VERSION 5.7 ;
  NOWIREEXTENSIONATPIN ON ;
  DIVIDERCHAR "/" ;
  BUSBITCHARS "[]" ;
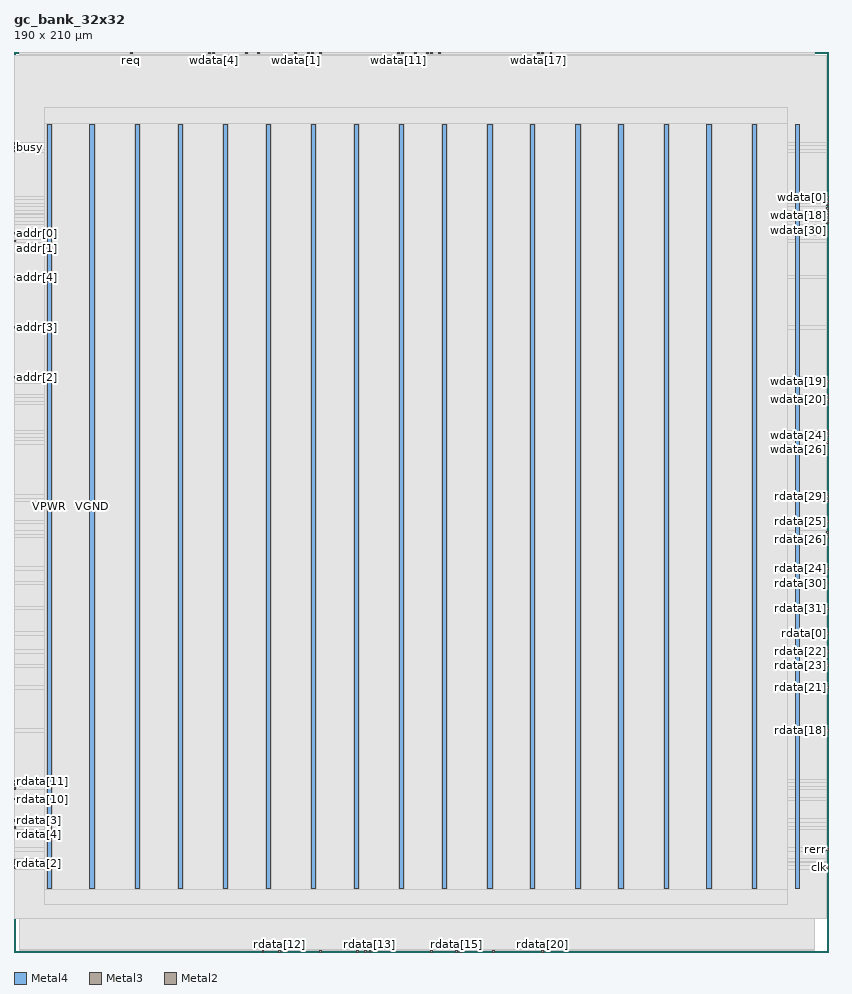
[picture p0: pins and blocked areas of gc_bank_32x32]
MACRO gc_bank_32x32
  CLASS BLOCK ;
  FOREIGN gc_bank_32x32 ;
  ORIGIN 0.000 0.000 ;
  SIZE 190.000 BY 210.000 ;
  PIN VGND
    DIRECTION INOUT ;
    USE GROUND ;
    PORT
      LAYER Metal4 ;
        RECT 17.710 14.900 18.710 193.000 ;
    END
    PORT
      LAYER Metal4 ;
        RECT 38.280 14.900 39.280 193.000 ;
    END
    PORT
      LAYER Metal4 ;
        RECT 58.850 14.900 59.850 193.000 ;
    END
    PORT
      LAYER Metal4 ;
        RECT 79.420 14.900 80.420 193.000 ;
    END
    PORT
      LAYER Metal4 ;
        RECT 99.990 14.900 100.990 193.000 ;
    END
    PORT
      LAYER Metal4 ;
        RECT 120.560 14.900 121.560 193.000 ;
    END
    PORT
      LAYER Metal4 ;
        RECT 141.130 14.900 142.130 193.000 ;
    END
    PORT
      LAYER Metal4 ;
        RECT 161.700 14.900 162.700 193.000 ;
    END
    PORT
      LAYER Metal4 ;
        RECT 182.270 14.900 183.270 193.000 ;
    END
  END VGND
  PIN VPWR
    DIRECTION INOUT ;
    USE POWER ;
    PORT
      LAYER Metal4 ;
        RECT 7.710 14.900 8.710 193.000 ;
    END
    PORT
      LAYER Metal4 ;
        RECT 28.280 14.900 29.280 193.000 ;
    END
    PORT
      LAYER Metal4 ;
        RECT 48.850 14.900 49.850 193.000 ;
    END
    PORT
      LAYER Metal4 ;
        RECT 69.420 14.900 70.420 193.000 ;
    END
    PORT
      LAYER Metal4 ;
        RECT 89.990 14.900 90.990 193.000 ;
    END
    PORT
      LAYER Metal4 ;
        RECT 110.560 14.900 111.560 193.000 ;
    END
    PORT
      LAYER Metal4 ;
        RECT 131.130 14.900 132.130 193.000 ;
    END
    PORT
      LAYER Metal4 ;
        RECT 151.700 14.900 152.700 193.000 ;
    END
    PORT
      LAYER Metal4 ;
        RECT 172.270 14.900 173.270 193.000 ;
    END
  END VPWR
  PIN addr[0]
    DIRECTION INPUT ;
    USE SIGNAL ;
    ANTENNAGATEAREA 0.180700 ;
    PORT
      LAYER Metal3 ;
        RECT 0.000 167.380 0.400 167.780 ;
    END
  END addr[0]
  PIN addr[1]
    DIRECTION INPUT ;
    USE SIGNAL ;
    ANTENNAGATEAREA 0.180700 ;
    PORT
      LAYER Metal3 ;
        RECT 0.000 165.700 0.400 166.100 ;
    END
  END addr[1]
  PIN addr[2]
    DIRECTION INPUT ;
    USE SIGNAL ;
    ANTENNAGATEAREA 0.180700 ;
    PORT
      LAYER Metal3 ;
        RECT 0.000 133.780 0.400 134.180 ;
    END
  END addr[2]
  PIN addr[3]
    DIRECTION INPUT ;
    USE SIGNAL ;
    ANTENNAGATEAREA 0.180700 ;
    PORT
      LAYER Metal3 ;
        RECT 0.000 145.540 0.400 145.940 ;
    END
  END addr[3]
  PIN addr[4]
    DIRECTION INPUT ;
    USE SIGNAL ;
    ANTENNAGATEAREA 0.180700 ;
    PORT
      LAYER Metal3 ;
        RECT 0.000 157.300 0.400 157.700 ;
    END
  END addr[4]
  PIN busy
    DIRECTION OUTPUT ;
    USE SIGNAL ;
    ANTENNADIFFAREA 0.708600 ;
    PORT
      LAYER Metal3 ;
        RECT 0.000 187.540 0.400 187.940 ;
    END
  END busy
  PIN clk
    DIRECTION INPUT ;
    USE SIGNAL ;
    ANTENNAGATEAREA 0.725400 ;
    PORT
      LAYER Metal3 ;
        RECT 189.600 19.540 190.000 19.940 ;
    END
  END clk
  PIN rdata[0]
    DIRECTION OUTPUT ;
    USE SIGNAL ;
    ANTENNADIFFAREA 0.708600 ;
    PORT
      LAYER Metal3 ;
        RECT 189.600 74.140 190.000 74.540 ;
    END
  END rdata[0]
  PIN rdata[10]
    DIRECTION OUTPUT ;
    USE SIGNAL ;
    ANTENNADIFFAREA 0.708600 ;
    PORT
      LAYER Metal3 ;
        RECT 0.000 35.500 0.400 35.900 ;
    END
  END rdata[10]
  PIN rdata[11]
    DIRECTION OUTPUT ;
    USE SIGNAL ;
    ANTENNADIFFAREA 0.708600 ;
    PORT
      LAYER Metal3 ;
        RECT 0.000 38.020 0.400 38.420 ;
    END
  END rdata[11]
  PIN rdata[12]
    DIRECTION OUTPUT ;
    USE SIGNAL ;
    ANTENNADIFFAREA 0.708600 ;
    PORT
      LAYER Metal2 ;
        RECT 61.720 0.000 62.120 0.400 ;
    END
  END rdata[12]
  PIN rdata[13]
    DIRECTION OUTPUT ;
    USE SIGNAL ;
    ANTENNADIFFAREA 0.708600 ;
    PORT
      LAYER Metal2 ;
        RECT 82.840 0.000 83.240 0.400 ;
    END
  END rdata[13]
  PIN rdata[14]
    DIRECTION OUTPUT ;
    USE SIGNAL ;
    ANTENNADIFFAREA 0.708600 ;
    PORT
      LAYER Metal2 ;
        RECT 81.880 0.000 82.280 0.400 ;
    END
  END rdata[14]
  PIN rdata[15]
    DIRECTION OUTPUT ;
    USE SIGNAL ;
    ANTENNADIFFAREA 0.708600 ;
    PORT
      LAYER Metal2 ;
        RECT 103.000 0.000 103.400 0.400 ;
    END
  END rdata[15]
  PIN rdata[16]
    DIRECTION OUTPUT ;
    USE SIGNAL ;
    ANTENNADIFFAREA 0.708600 ;
    PORT
      LAYER Metal2 ;
        RECT 97.240 0.000 97.640 0.400 ;
    END
  END rdata[16]
  PIN rdata[17]
    DIRECTION OUTPUT ;
    USE SIGNAL ;
    ANTENNADIFFAREA 0.708600 ;
    PORT
      LAYER Metal2 ;
        RECT 103.960 0.000 104.360 0.400 ;
    END
  END rdata[17]
  PIN rdata[18]
    DIRECTION OUTPUT ;
    USE SIGNAL ;
    ANTENNADIFFAREA 0.708600 ;
    PORT
      LAYER Metal3 ;
        RECT 189.600 51.460 190.000 51.860 ;
    END
  END rdata[18]
  PIN rdata[19]
    DIRECTION OUTPUT ;
    USE SIGNAL ;
    ANTENNADIFFAREA 0.708600 ;
    PORT
      LAYER Metal2 ;
        RECT 111.640 0.000 112.040 0.400 ;
    END
  END rdata[19]
  PIN rdata[1]
    DIRECTION OUTPUT ;
    USE SIGNAL ;
    ANTENNADIFFAREA 0.708600 ;
    PORT
      LAYER Metal2 ;
        RECT 79.960 0.000 80.360 0.400 ;
    END
  END rdata[1]
  PIN rdata[20]
    DIRECTION OUTPUT ;
    USE SIGNAL ;
    ANTENNADIFFAREA 0.708600 ;
    PORT
      LAYER Metal2 ;
        RECT 123.160 0.000 123.560 0.400 ;
    END
  END rdata[20]
  PIN rdata[21]
    DIRECTION OUTPUT ;
    USE SIGNAL ;
    ANTENNADIFFAREA 0.708600 ;
    PORT
      LAYER Metal3 ;
        RECT 189.600 61.540 190.000 61.940 ;
    END
  END rdata[21]
  PIN rdata[22]
    DIRECTION OUTPUT ;
    USE SIGNAL ;
    ANTENNADIFFAREA 0.708600 ;
    PORT
      LAYER Metal3 ;
        RECT 189.600 69.940 190.000 70.340 ;
    END
  END rdata[22]
  PIN rdata[23]
    DIRECTION OUTPUT ;
    USE SIGNAL ;
    ANTENNADIFFAREA 0.708600 ;
    PORT
      LAYER Metal3 ;
        RECT 189.600 66.580 190.000 66.980 ;
    END
  END rdata[23]
  PIN rdata[24]
    DIRECTION OUTPUT ;
    USE SIGNAL ;
    ANTENNADIFFAREA 0.708600 ;
    PORT
      LAYER Metal3 ;
        RECT 189.600 89.260 190.000 89.660 ;
    END
  END rdata[24]
  PIN rdata[25]
    DIRECTION OUTPUT ;
    USE SIGNAL ;
    ANTENNADIFFAREA 0.708600 ;
    PORT
      LAYER Metal3 ;
        RECT 189.600 100.180 190.000 100.580 ;
    END
  END rdata[25]
  PIN rdata[26]
    DIRECTION OUTPUT ;
    USE SIGNAL ;
    ANTENNADIFFAREA 0.708600 ;
    PORT
      LAYER Metal3 ;
        RECT 189.600 97.660 190.000 98.060 ;
    END
  END rdata[26]
  PIN rdata[27]
    DIRECTION OUTPUT ;
    USE SIGNAL ;
    ANTENNADIFFAREA 0.708600 ;
    PORT
      LAYER Metal3 ;
        RECT 189.600 96.820 190.000 97.220 ;
    END
  END rdata[27]
  PIN rdata[28]
    DIRECTION OUTPUT ;
    USE SIGNAL ;
    ANTENNADIFFAREA 0.708600 ;
    PORT
      LAYER Metal3 ;
        RECT 189.600 105.220 190.000 105.620 ;
    END
  END rdata[28]
  PIN rdata[29]
    DIRECTION OUTPUT ;
    USE SIGNAL ;
    ANTENNADIFFAREA 0.708600 ;
    PORT
      LAYER Metal3 ;
        RECT 189.600 106.060 190.000 106.460 ;
    END
  END rdata[29]
  PIN rdata[2]
    DIRECTION OUTPUT ;
    USE SIGNAL ;
    ANTENNADIFFAREA 0.708600 ;
    PORT
      LAYER Metal3 ;
        RECT 0.000 20.380 0.400 20.780 ;
    END
  END rdata[2]
  PIN rdata[30]
    DIRECTION OUTPUT ;
    USE SIGNAL ;
    ANTENNADIFFAREA 0.708600 ;
    PORT
      LAYER Metal3 ;
        RECT 189.600 85.900 190.000 86.300 ;
    END
  END rdata[30]
  PIN rdata[31]
    DIRECTION OUTPUT ;
    USE SIGNAL ;
    ANTENNADIFFAREA 0.708600 ;
    PORT
      LAYER Metal3 ;
        RECT 189.600 80.020 190.000 80.420 ;
    END
  END rdata[31]
  PIN rdata[3]
    DIRECTION OUTPUT ;
    USE SIGNAL ;
    ANTENNADIFFAREA 0.708600 ;
    PORT
      LAYER Metal3 ;
        RECT 0.000 30.460 0.400 30.860 ;
    END
  END rdata[3]
  PIN rdata[4]
    DIRECTION OUTPUT ;
    USE SIGNAL ;
    ANTENNADIFFAREA 0.708600 ;
    PORT
      LAYER Metal3 ;
        RECT 0.000 28.780 0.400 29.180 ;
    END
  END rdata[4]
  PIN rdata[5]
    DIRECTION OUTPUT ;
    USE SIGNAL ;
    ANTENNADIFFAREA 0.708600 ;
    PORT
      LAYER Metal3 ;
        RECT 0.000 21.220 0.400 21.620 ;
    END
  END rdata[5]
  PIN rdata[6]
    DIRECTION OUTPUT ;
    USE SIGNAL ;
    ANTENNADIFFAREA 0.708600 ;
    PORT
      LAYER Metal2 ;
        RECT 71.320 0.000 71.720 0.400 ;
    END
  END rdata[6]
  PIN rdata[7]
    DIRECTION OUTPUT ;
    USE SIGNAL ;
    ANTENNADIFFAREA 0.708600 ;
    PORT
      LAYER Metal2 ;
        RECT 57.880 0.000 58.280 0.400 ;
    END
  END rdata[7]
  PIN rdata[8]
    DIRECTION OUTPUT ;
    USE SIGNAL ;
    ANTENNADIFFAREA 0.708600 ;
    PORT
      LAYER Metal3 ;
        RECT 0.000 19.540 0.400 19.940 ;
    END
  END rdata[8]
  PIN rdata[9]
    DIRECTION OUTPUT ;
    USE SIGNAL ;
    ANTENNADIFFAREA 0.708600 ;
    PORT
      LAYER Metal3 ;
        RECT 0.000 38.860 0.400 39.260 ;
    END
  END rdata[9]
  PIN req
    DIRECTION INPUT ;
    USE SIGNAL ;
    ANTENNAGATEAREA 0.180700 ;
    PORT
      LAYER Metal2 ;
        RECT 27.160 209.600 27.560 210.000 ;
    END
  END req
  PIN rerr
    DIRECTION OUTPUT ;
    USE SIGNAL ;
    ANTENNADIFFAREA 0.708600 ;
    PORT
      LAYER Metal3 ;
        RECT 189.600 23.740 190.000 24.140 ;
    END
  END rerr
  PIN rst_n
    DIRECTION INPUT ;
    USE SIGNAL ;
    ANTENNAGATEAREA 0.180700 ;
    PORT
      LAYER Metal3 ;
        RECT 0.000 186.700 0.400 187.100 ;
    END
  END rst_n
  PIN rvalid
    DIRECTION OUTPUT ;
    USE SIGNAL ;
    ANTENNADIFFAREA 0.708600 ;
    PORT
      LAYER Metal3 ;
        RECT 0.000 39.700 0.400 40.100 ;
    END
  END rvalid
  PIN wdata[0]
    DIRECTION INPUT ;
    USE SIGNAL ;
    ANTENNAGATEAREA 0.180700 ;
    PORT
      LAYER Metal3 ;
        RECT 189.600 175.780 190.000 176.180 ;
    END
  END wdata[0]
  PIN wdata[10]
    DIRECTION INPUT ;
    USE SIGNAL ;
    ANTENNAGATEAREA 0.180700 ;
    PORT
      LAYER Metal2 ;
        RECT 90.520 209.600 90.920 210.000 ;
    END
  END wdata[10]
  PIN wdata[11]
    DIRECTION INPUT ;
    USE SIGNAL ;
    ANTENNAGATEAREA 0.180700 ;
    PORT
      LAYER Metal2 ;
        RECT 89.560 209.600 89.960 210.000 ;
    END
  END wdata[11]
  PIN wdata[12]
    DIRECTION INPUT ;
    USE SIGNAL ;
    ANTENNAGATEAREA 0.180700 ;
    PORT
      LAYER Metal2 ;
        RECT 99.160 209.600 99.560 210.000 ;
    END
  END wdata[12]
  PIN wdata[13]
    DIRECTION INPUT ;
    USE SIGNAL ;
    ANTENNAGATEAREA 0.180700 ;
    PORT
      LAYER Metal2 ;
        RECT 97.240 209.600 97.640 210.000 ;
    END
  END wdata[13]
  PIN wdata[14]
    DIRECTION INPUT ;
    USE SIGNAL ;
    ANTENNAGATEAREA 0.180700 ;
    PORT
      LAYER Metal2 ;
        RECT 96.280 209.600 96.680 210.000 ;
    END
  END wdata[14]
  PIN wdata[15]
    DIRECTION INPUT ;
    USE SIGNAL ;
    ANTENNAGATEAREA 0.180700 ;
    PORT
      LAYER Metal2 ;
        RECT 125.080 209.600 125.480 210.000 ;
    END
  END wdata[15]
  PIN wdata[16]
    DIRECTION INPUT ;
    USE SIGNAL ;
    ANTENNAGATEAREA 0.180700 ;
    PORT
      LAYER Metal2 ;
        RECT 123.160 209.600 123.560 210.000 ;
    END
  END wdata[16]
  PIN wdata[17]
    DIRECTION INPUT ;
    USE SIGNAL ;
    ANTENNAGATEAREA 0.180700 ;
    PORT
      LAYER Metal2 ;
        RECT 122.200 209.600 122.600 210.000 ;
    END
  END wdata[17]
  PIN wdata[18]
    DIRECTION INPUT ;
    USE SIGNAL ;
    ANTENNAGATEAREA 0.180700 ;
    PORT
      LAYER Metal3 ;
        RECT 189.600 171.580 190.000 171.980 ;
    END
  END wdata[18]
  PIN wdata[19]
    DIRECTION INPUT ;
    USE SIGNAL ;
    ANTENNAGATEAREA 0.180700 ;
    PORT
      LAYER Metal3 ;
        RECT 189.600 132.940 190.000 133.340 ;
    END
  END wdata[19]
  PIN wdata[1]
    DIRECTION INPUT ;
    USE SIGNAL ;
    ANTENNAGATEAREA 0.180700 ;
    PORT
      LAYER Metal2 ;
        RECT 65.560 209.600 65.960 210.000 ;
    END
  END wdata[1]
  PIN wdata[20]
    DIRECTION INPUT ;
    USE SIGNAL ;
    ANTENNAGATEAREA 0.180700 ;
    PORT
      LAYER Metal3 ;
        RECT 189.600 128.740 190.000 129.140 ;
    END
  END wdata[20]
  PIN wdata[21]
    DIRECTION INPUT ;
    USE SIGNAL ;
    ANTENNAGATEAREA 0.180700 ;
    PORT
      LAYER Metal3 ;
        RECT 189.600 173.260 190.000 173.660 ;
    END
  END wdata[21]
  PIN wdata[22]
    DIRECTION INPUT ;
    USE SIGNAL ;
    ANTENNAGATEAREA 0.180700 ;
    PORT
      LAYER Metal3 ;
        RECT 189.600 170.740 190.000 171.140 ;
    END
  END wdata[22]
  PIN wdata[23]
    DIRECTION INPUT ;
    USE SIGNAL ;
    ANTENNAGATEAREA 0.180700 ;
    PORT
      LAYER Metal3 ;
        RECT 189.600 174.100 190.000 174.500 ;
    END
  END wdata[23]
  PIN wdata[24]
    DIRECTION INPUT ;
    USE SIGNAL ;
    ANTENNAGATEAREA 0.180700 ;
    PORT
      LAYER Metal3 ;
        RECT 189.600 120.340 190.000 120.740 ;
    END
  END wdata[24]
  PIN wdata[25]
    DIRECTION INPUT ;
    USE SIGNAL ;
    ANTENNAGATEAREA 0.180700 ;
    PORT
      LAYER Metal3 ;
        RECT 189.600 121.180 190.000 121.580 ;
    END
  END wdata[25]
  PIN wdata[26]
    DIRECTION INPUT ;
    USE SIGNAL ;
    ANTENNAGATEAREA 0.180700 ;
    PORT
      LAYER Metal3 ;
        RECT 189.600 118.660 190.000 119.060 ;
    END
  END wdata[26]
  PIN wdata[27]
    DIRECTION INPUT ;
    USE SIGNAL ;
    ANTENNAGATEAREA 0.180700 ;
    PORT
      LAYER Metal3 ;
        RECT 189.600 174.940 190.000 175.340 ;
    END
  END wdata[27]
  PIN wdata[28]
    DIRECTION INPUT ;
    USE SIGNAL ;
    ANTENNAGATEAREA 0.180700 ;
    PORT
      LAYER Metal3 ;
        RECT 189.600 129.580 190.000 129.980 ;
    END
  END wdata[28]
  PIN wdata[29]
    DIRECTION INPUT ;
    USE SIGNAL ;
    ANTENNAGATEAREA 0.180700 ;
    PORT
      LAYER Metal3 ;
        RECT 189.600 127.900 190.000 128.300 ;
    END
  END wdata[29]
  PIN wdata[2]
    DIRECTION INPUT ;
    USE SIGNAL ;
    ANTENNAGATEAREA 0.180700 ;
    PORT
      LAYER Metal2 ;
        RECT 56.920 209.600 57.320 210.000 ;
    END
  END wdata[2]
  PIN wdata[30]
    DIRECTION INPUT ;
    USE SIGNAL ;
    ANTENNAGATEAREA 0.180700 ;
    PORT
      LAYER Metal3 ;
        RECT 189.600 169.900 190.000 170.300 ;
    END
  END wdata[30]
  PIN wdata[31]
    DIRECTION INPUT ;
    USE SIGNAL ;
    ANTENNAGATEAREA 0.180700 ;
    PORT
      LAYER Metal3 ;
        RECT 189.600 172.420 190.000 172.820 ;
    END
  END wdata[31]
  PIN wdata[3]
    DIRECTION INPUT ;
    USE SIGNAL ;
    ANTENNAGATEAREA 0.180700 ;
    PORT
      LAYER Metal2 ;
        RECT 54.040 209.600 54.440 210.000 ;
    END
  END wdata[3]
  PIN wdata[4]
    DIRECTION INPUT ;
    USE SIGNAL ;
    ANTENNAGATEAREA 0.180700 ;
    PORT
      LAYER Metal2 ;
        RECT 46.360 209.600 46.760 210.000 ;
    END
  END wdata[4]
  PIN wdata[5]
    DIRECTION INPUT ;
    USE SIGNAL ;
    ANTENNAGATEAREA 0.180700 ;
    PORT
      LAYER Metal2 ;
        RECT 45.400 209.600 45.800 210.000 ;
    END
  END wdata[5]
  PIN wdata[6]
    DIRECTION INPUT ;
    USE SIGNAL ;
    ANTENNAGATEAREA 0.180700 ;
    PORT
      LAYER Metal2 ;
        RECT 71.320 209.600 71.720 210.000 ;
    END
  END wdata[6]
  PIN wdata[7]
    DIRECTION INPUT ;
    USE SIGNAL ;
    ANTENNAGATEAREA 0.180700 ;
    PORT
      LAYER Metal2 ;
        RECT 69.400 209.600 69.800 210.000 ;
    END
  END wdata[7]
  PIN wdata[8]
    DIRECTION INPUT ;
    USE SIGNAL ;
    ANTENNAGATEAREA 0.180700 ;
    PORT
      LAYER Metal2 ;
        RECT 68.440 209.600 68.840 210.000 ;
    END
  END wdata[8]
  PIN wdata[9]
    DIRECTION INPUT ;
    USE SIGNAL ;
    ANTENNAGATEAREA 0.180700 ;
    PORT
      LAYER Metal2 ;
        RECT 93.400 209.600 93.800 210.000 ;
    END
  END wdata[9]
  PIN we
    DIRECTION INPUT ;
    USE SIGNAL ;
    ANTENNAGATEAREA 0.180700 ;
    PORT
      LAYER Metal3 ;
        RECT 0.000 188.380 0.400 188.780 ;
    END
  END we
  OBS
      LAYER GatPoly ;
        RECT 5.760 14.970 183.840 192.930 ;
      LAYER Metal1 ;
        RECT 5.760 14.900 183.840 193.000 ;
      LAYER Metal2 ;
        RECT 1.335 209.390 26.950 209.900 ;
        RECT 27.770 209.390 45.190 209.900 ;
        RECT 46.010 209.390 46.150 209.900 ;
        RECT 46.970 209.390 53.830 209.900 ;
        RECT 54.650 209.390 56.710 209.900 ;
        RECT 57.530 209.390 65.350 209.900 ;
        RECT 66.170 209.390 68.230 209.900 ;
        RECT 69.050 209.390 69.190 209.900 ;
        RECT 70.010 209.390 71.110 209.900 ;
        RECT 71.930 209.390 89.350 209.900 ;
        RECT 90.170 209.390 90.310 209.900 ;
        RECT 91.130 209.390 93.190 209.900 ;
        RECT 94.010 209.390 96.070 209.900 ;
        RECT 96.890 209.390 97.030 209.900 ;
        RECT 97.850 209.390 98.950 209.900 ;
        RECT 99.770 209.390 121.990 209.900 ;
        RECT 122.810 209.390 122.950 209.900 ;
        RECT 123.770 209.390 124.870 209.900 ;
        RECT 125.690 209.390 186.825 209.900 ;
        RECT 1.335 0.610 186.825 209.390 ;
        RECT 1.335 0.400 57.670 0.610 ;
        RECT 58.490 0.400 61.510 0.610 ;
        RECT 62.330 0.400 71.110 0.610 ;
        RECT 71.930 0.400 79.750 0.610 ;
        RECT 80.570 0.400 81.670 0.610 ;
        RECT 82.490 0.400 82.630 0.610 ;
        RECT 83.450 0.400 97.030 0.610 ;
        RECT 97.850 0.400 102.790 0.610 ;
        RECT 103.610 0.400 103.750 0.610 ;
        RECT 104.570 0.400 111.430 0.610 ;
        RECT 112.250 0.400 122.950 0.610 ;
        RECT 123.770 0.400 186.825 0.610 ;
      LAYER Metal3 ;
        RECT 0.100 188.990 189.600 209.260 ;
        RECT 0.610 188.170 189.600 188.990 ;
        RECT 0.100 188.150 189.600 188.170 ;
        RECT 0.610 187.330 189.600 188.150 ;
        RECT 0.100 187.310 189.600 187.330 ;
        RECT 0.610 186.490 189.600 187.310 ;
        RECT 0.100 176.390 189.600 186.490 ;
        RECT 0.100 175.570 189.390 176.390 ;
        RECT 0.100 175.550 189.600 175.570 ;
        RECT 0.100 174.730 189.390 175.550 ;
        RECT 0.100 174.710 189.600 174.730 ;
        RECT 0.100 173.890 189.390 174.710 ;
        RECT 0.100 173.870 189.600 173.890 ;
        RECT 0.100 173.050 189.390 173.870 ;
        RECT 0.100 173.030 189.600 173.050 ;
        RECT 0.100 172.210 189.390 173.030 ;
        RECT 0.100 172.190 189.600 172.210 ;
        RECT 0.100 171.370 189.390 172.190 ;
        RECT 0.100 171.350 189.600 171.370 ;
        RECT 0.100 170.530 189.390 171.350 ;
        RECT 0.100 170.510 189.600 170.530 ;
        RECT 0.100 169.690 189.390 170.510 ;
        RECT 0.100 167.990 189.600 169.690 ;
        RECT 0.610 167.170 189.600 167.990 ;
        RECT 0.100 166.310 189.600 167.170 ;
        RECT 0.610 165.490 189.600 166.310 ;
        RECT 0.100 157.910 189.600 165.490 ;
        RECT 0.610 157.090 189.600 157.910 ;
        RECT 0.100 146.150 189.600 157.090 ;
        RECT 0.610 145.330 189.600 146.150 ;
        RECT 0.100 134.390 189.600 145.330 ;
        RECT 0.610 133.570 189.600 134.390 ;
        RECT 0.100 133.550 189.600 133.570 ;
        RECT 0.100 132.730 189.390 133.550 ;
        RECT 0.100 130.190 189.600 132.730 ;
        RECT 0.100 129.370 189.390 130.190 ;
        RECT 0.100 129.350 189.600 129.370 ;
        RECT 0.100 128.530 189.390 129.350 ;
        RECT 0.100 128.510 189.600 128.530 ;
        RECT 0.100 127.690 189.390 128.510 ;
        RECT 0.100 121.790 189.600 127.690 ;
        RECT 0.100 120.970 189.390 121.790 ;
        RECT 0.100 120.950 189.600 120.970 ;
        RECT 0.100 120.130 189.390 120.950 ;
        RECT 0.100 119.270 189.600 120.130 ;
        RECT 0.100 118.450 189.390 119.270 ;
        RECT 0.100 106.670 189.600 118.450 ;
        RECT 0.100 105.850 189.390 106.670 ;
        RECT 0.100 105.830 189.600 105.850 ;
        RECT 0.100 105.010 189.390 105.830 ;
        RECT 0.100 100.790 189.600 105.010 ;
        RECT 0.100 99.970 189.390 100.790 ;
        RECT 0.100 98.270 189.600 99.970 ;
        RECT 0.100 97.450 189.390 98.270 ;
        RECT 0.100 97.430 189.600 97.450 ;
        RECT 0.100 96.610 189.390 97.430 ;
        RECT 0.100 89.870 189.600 96.610 ;
        RECT 0.100 89.050 189.390 89.870 ;
        RECT 0.100 86.510 189.600 89.050 ;
        RECT 0.100 85.690 189.390 86.510 ;
        RECT 0.100 80.630 189.600 85.690 ;
        RECT 0.100 79.810 189.390 80.630 ;
        RECT 0.100 74.750 189.600 79.810 ;
        RECT 0.100 73.930 189.390 74.750 ;
        RECT 0.100 70.550 189.600 73.930 ;
        RECT 0.100 69.730 189.390 70.550 ;
        RECT 0.100 67.190 189.600 69.730 ;
        RECT 0.100 66.370 189.390 67.190 ;
        RECT 0.100 62.150 189.600 66.370 ;
        RECT 0.100 61.330 189.390 62.150 ;
        RECT 0.100 52.070 189.600 61.330 ;
        RECT 0.100 51.250 189.390 52.070 ;
        RECT 0.100 40.310 189.600 51.250 ;
        RECT 0.610 39.490 189.600 40.310 ;
        RECT 0.100 39.470 189.600 39.490 ;
        RECT 0.610 38.650 189.600 39.470 ;
        RECT 0.100 38.630 189.600 38.650 ;
        RECT 0.610 37.810 189.600 38.630 ;
        RECT 0.100 36.110 189.600 37.810 ;
        RECT 0.610 35.290 189.600 36.110 ;
        RECT 0.100 31.070 189.600 35.290 ;
        RECT 0.610 30.250 189.600 31.070 ;
        RECT 0.100 29.390 189.600 30.250 ;
        RECT 0.610 28.570 189.600 29.390 ;
        RECT 0.100 24.350 189.600 28.570 ;
        RECT 0.100 23.530 189.390 24.350 ;
        RECT 0.100 21.830 189.600 23.530 ;
        RECT 0.610 21.010 189.600 21.830 ;
        RECT 0.100 20.990 189.600 21.010 ;
        RECT 0.610 20.170 189.600 20.990 ;
        RECT 0.100 20.150 189.600 20.170 ;
        RECT 0.610 19.330 189.390 20.150 ;
        RECT 0.100 7.880 189.600 19.330 ;
      LAYER Metal4 ;
        RECT 7.100 193.210 180.580 197.125 ;
        RECT 7.100 14.690 7.500 193.210 ;
        RECT 8.920 14.690 17.500 193.210 ;
        RECT 18.920 14.690 28.070 193.210 ;
        RECT 29.490 14.690 38.070 193.210 ;
        RECT 39.490 14.690 48.640 193.210 ;
        RECT 50.060 14.690 58.640 193.210 ;
        RECT 60.060 14.690 69.210 193.210 ;
        RECT 70.630 14.690 79.210 193.210 ;
        RECT 80.630 14.690 89.780 193.210 ;
        RECT 91.200 14.690 99.780 193.210 ;
        RECT 101.200 14.690 110.350 193.210 ;
        RECT 111.770 14.690 120.350 193.210 ;
        RECT 121.770 14.690 130.920 193.210 ;
        RECT 132.340 14.690 140.920 193.210 ;
        RECT 142.340 14.690 151.490 193.210 ;
        RECT 152.910 14.690 161.490 193.210 ;
        RECT 162.910 14.690 172.060 193.210 ;
        RECT 173.480 14.690 180.580 193.210 ;
        RECT 7.100 11.195 180.580 14.690 ;
  END
END gc_bank_32x32
END LIBRARY

